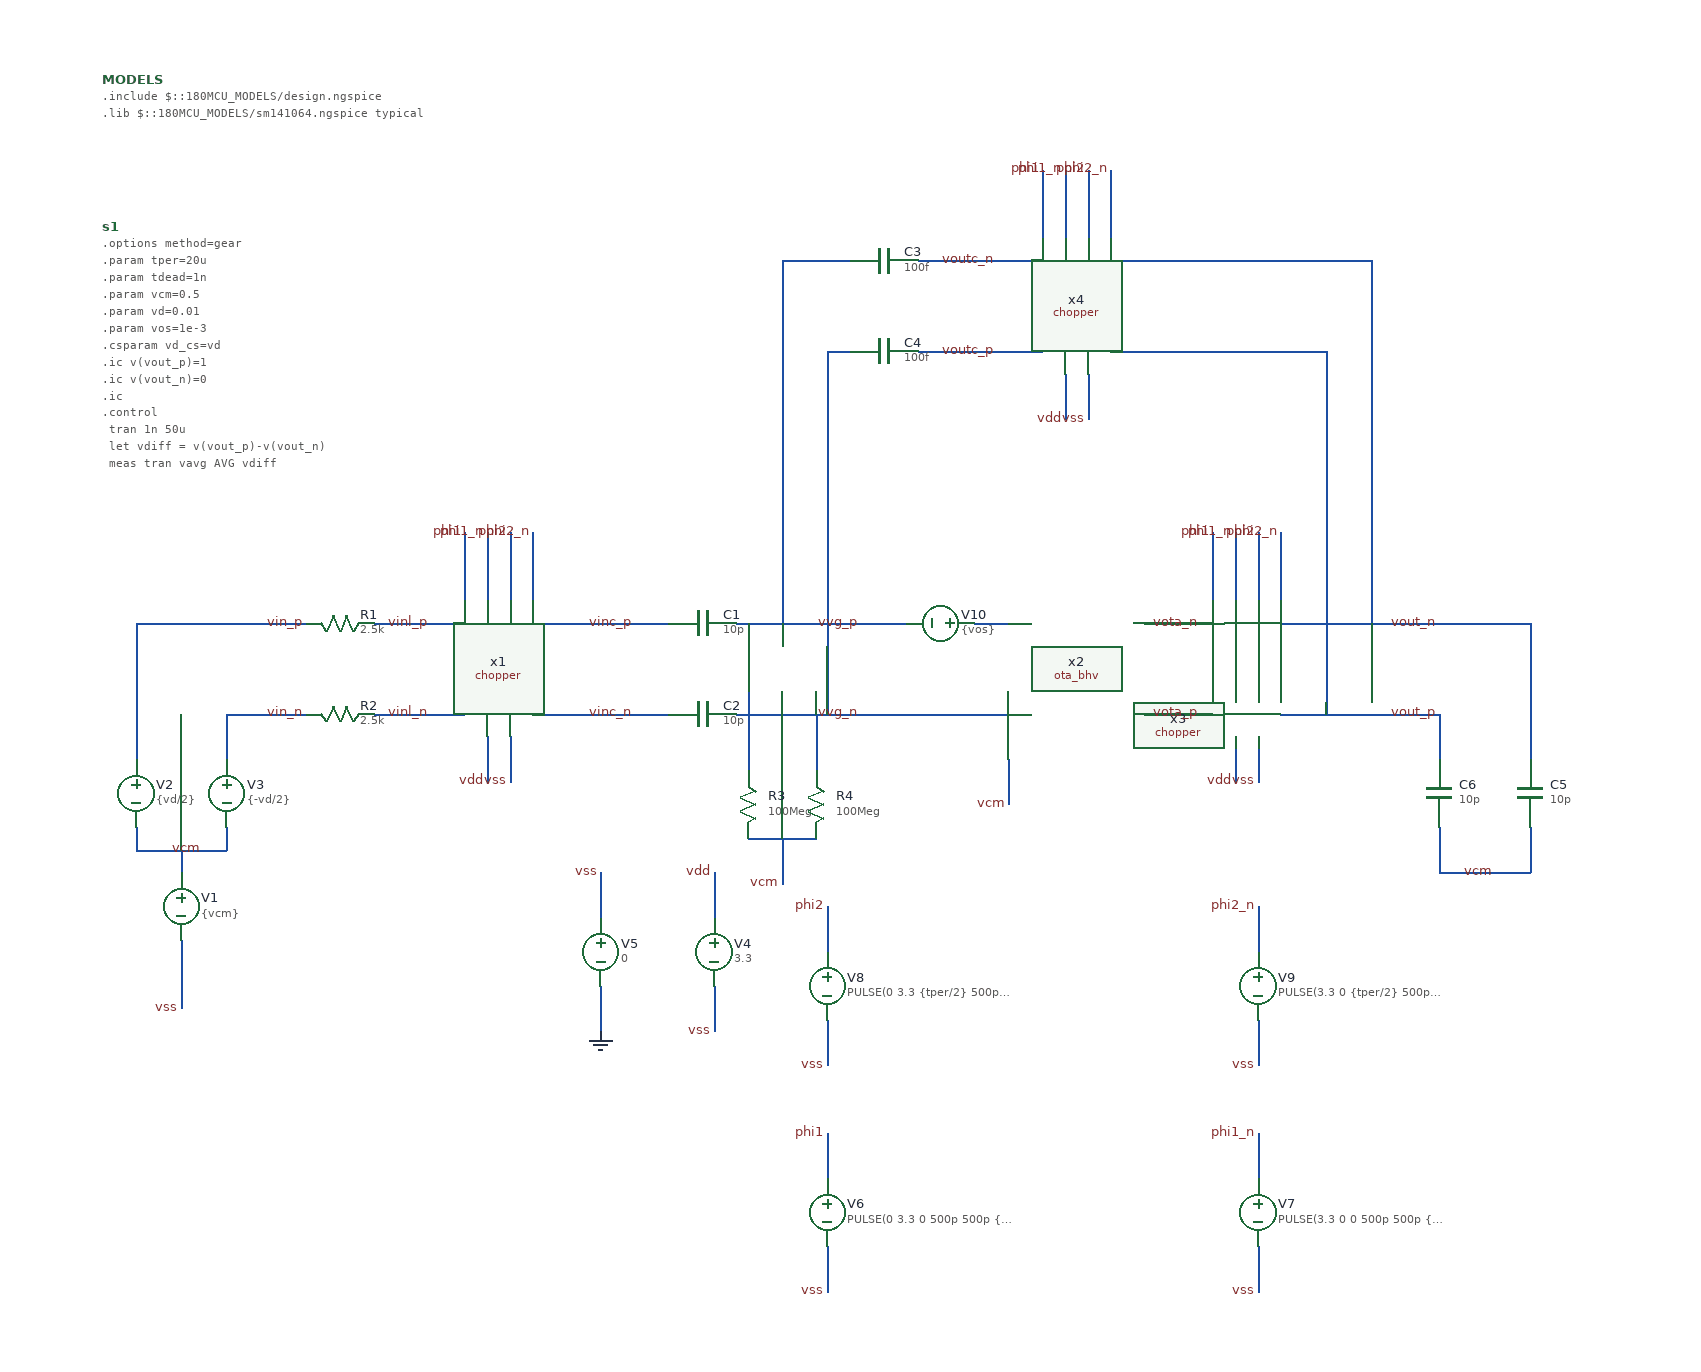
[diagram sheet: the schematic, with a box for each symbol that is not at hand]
v {xschem version=3.4.8RC file_version=1.3}
G {}
K {}
V {}
S {}
F {}
E {}
N 640 -160 860 -160 {lab=vout_n}
N 860 -160 860 -40 {lab=vout_n}
N 780 -80 780 -40 {lab=vout_p}
N 640 -80 780 -80 {lab=vout_p}
N 780 20 780 60 {lab=vcm}
N 780 60 860 60 {lab=vcm}
N 860 20 860 60 {lab=vcm}
N 400 -40 400 0 {lab=vcm}
N 520 -160 580 -160 {lab=vota_n}
N 520 -80 580 -80 {lab=vota_p}
N 160 -160 280 -160 {lab=vvg_p}
N 60 -160 100 -160 {lab=vinc_p}
N 60 -80 100 -80 {lab=vinc_n}
N 160 -80 280 -80 {lab=vvg_n}
N 720 -480 720 -160 {lab=vout_n}
N 680 -400 680 -80 {lab=vout_p}
N 320 -480 380 -480 {lab=voutc_n}
N 320 -400 380 -400 {lab=voutc_p}
N 200 -480 260 -480 {lab=vvg_p}
N 200 -480 200 -160 {lab=vvg_p}
N 240 -400 260 -400 {lab=vvg_n}
N 240 -400 240 -80 {lab=vvg_n}
N -60 -60 -60 -20 {lab=vdd}
N -40 -60 -40 -20 {lab=vss}
N 600 -60 600 -20 {lab=vdd}
N 620 -60 620 -20 {lab=vss}
N 450 -380 450 -340 {lab=vdd}
N 470 -380 470 -340 {lab=vss}
N -80 -220 -80 -180 {lab=phi1}
N -60 -220 -60 -180 {lab=phi1_n}
N -80 -240 -80 -220 {lab=phi1}
N -60 -240 -60 -220 {lab=phi1_n}
N -40 -220 -40 -180 {lab=phi2}
N -20 -220 -20 -180 {lab=phi2_n}
N -40 -240 -40 -220 {lab=phi2}
N -20 -240 -20 -220 {lab=phi2_n}
N 430 -540 430 -500 {lab=phi1}
N 450 -540 450 -500 {lab=phi1_n}
N 430 -560 430 -540 {lab=phi1}
N 450 -560 450 -540 {lab=phi1_n}
N 470 -540 470 -500 {lab=phi2}
N 490 -540 490 -500 {lab=phi2_n}
N 470 -560 470 -540 {lab=phi2}
N 490 -560 490 -540 {lab=phi2_n}
N 580 -220 580 -180 {lab=phi1}
N 600 -220 600 -180 {lab=phi1_n}
N 580 -240 580 -220 {lab=phi1}
N 600 -240 600 -220 {lab=phi1_n}
N 620 -220 620 -180 {lab=phi2}
N 640 -220 640 -180 {lab=phi2_n}
N 620 -240 620 -220 {lab=phi2}
N 640 -240 640 -220 {lab=phi2_n}
N -290 -80 -290 -40 {lab=vin_n}
N -290 -80 -230 -80 {lab=vin_n}
N -370 -160 -230 -160 {lab=vin_p}
N -370 -160 -370 -40 {lab=vin_p}
N -370 20 -370 40 {lab=vcm}
N -370 40 -290 40 {lab=vcm}
N -290 20 -290 40 {lab=vcm}
N -330 40 -330 60 {lab=vcm}
N -330 120 -330 180 {lab=vss}
N 140 160 140 180 {lab=vss}
N 140 180 140 200 {lab=vss}
N 140 60 140 100 {lab=vdd}
N 40 160 40 200 {lab=0}
N 40 80 40 100 {lab=vss}
N 40 60 40 80 {lab=vss}
N 240 390 240 410 {lab=vss}
N 240 410 240 430 {lab=vss}
N 240 290 240 330 {lab=phi1}
N 620 390 620 410 {lab=vss}
N 620 410 620 430 {lab=vss}
N 620 290 620 330 {lab=phi1_n}
N 240 190 240 210 {lab=vss}
N 240 210 240 230 {lab=vss}
N 240 90 240 130 {lab=phi2}
N 620 190 620 210 {lab=vss}
N 620 210 620 230 {lab=vss}
N 620 90 620 130 {lab=phi2_n}
N -230 -80 -220 -80 {lab=vin_n}
N -230 -160 -220 -160 {lab=vin_p}
N 170 30 230 30 {lab=vcm}
N 200 30 200 50 {lab=vcm}
N 200 50 200 70 {lab=vcm}
N 170 -160 170 -30 {lab=vvg_p}
N 230 -80 230 -30 {lab=vvg_n}
N 490 -480 600 -480 {lab=vout_n}
N 490 -400 560 -400 {lab=vout_p}
N 380 -400 420 -400 {lab=voutc_p}
N 420 -400 430 -400 {lab=voutc_p}
N 380 -480 430 -480 {lab=voutc_n}
N -160 -160 -80 -160 {lab=vinl_p}
N -160 -80 -80 -80 {lab=vinl_n}
N -20 -160 60 -160 {lab=vinc_p}
N -20 -80 60 -80 {lab=vinc_n}
N 280 -80 400 -80 {lab=vvg_n}
N 560 -400 680 -400 {lab=vout_p}
N 600 -480 720 -480 {lab=vout_n}
N 280 -160 310 -160 {lab=vvg_p}
N 370 -160 390 -160 {lab=#net1}
N 390 -160 400 -160 {lab=#net1}
C {chopper/chopper.sym} -80 -60 0 0 {name=x1}
C {ota_bhv/ota_bhv.sym} 400 -40 0 0 {name=x2 rout=1e6 dc_gain=1e6}
C {chopper/chopper.sym} 580 -60 0 0 {name=x3}
C {chopper/chopper.sym} 430 -380 0 0 {name=x4}
C {capa.sym} 130 -160 3 0 {name=C1
m=1
value=10p
footprint=1206
device="ceramic capacitor"}
C {capa.sym} 130 -80 3 0 {name=C2
m=1
value=10p
footprint=1206
device="ceramic capacitor"}
C {capa.sym} 290 -480 3 0 {name=C3
m=1
value=100f
footprint=1206
device="ceramic capacitor"}
C {capa.sym} 290 -400 3 0 {name=C4
m=1
value=100f
footprint=1206
device="ceramic capacitor"}
C {capa.sym} 860 -10 0 0 {name=C5
m=1
value=10p
footprint=1206
device="ceramic capacitor"}
C {capa.sym} 780 -10 0 0 {name=C6
m=1
value=10p

footprint=1206
device="ceramic capacitor"}
C {lab_wire.sym} 830 60 0 0 {name=p1 sig_type=std_logic lab=vcm}
C {lab_wire.sym} 400 0 1 0 {name=p2 sig_type=std_logic lab=vcm}
C {lab_wire.sym} 780 -160 0 0 {name=p3 sig_type=std_logic lab=vout_n}
C {lab_wire.sym} 780 -80 0 0 {name=p4 sig_type=std_logic lab=vout_p}
C {res.sym} -190 -160 1 0 {name=R1
value=2.5k
footprint=1206
device=resistor
m=1}
C {res.sym} -190 -80 1 0 {name=R2
value=2.5k
footprint=1206
device=resistor
m=1}
C {lab_wire.sym} -60 -20 3 1 {name=p5 sig_type=std_logic lab=vdd}
C {lab_wire.sym} -40 -20 3 1 {name=p6 sig_type=std_logic lab=vss}
C {lab_wire.sym} 600 -20 3 1 {name=p7 sig_type=std_logic lab=vdd}
C {lab_wire.sym} 620 -20 3 1 {name=p8 sig_type=std_logic lab=vss}
C {lab_wire.sym} 450 -340 3 1 {name=p9 sig_type=std_logic lab=vdd}
C {lab_wire.sym} 470 -340 3 1 {name=p10 sig_type=std_logic lab=vss}
C {lab_wire.sym} -80 -240 3 0 {name=p11 sig_type=std_logic lab=phi1}
C {lab_wire.sym} -60 -240 3 0 {name=p12 sig_type=std_logic lab=phi1_n}
C {lab_wire.sym} -40 -240 3 0 {name=p13 sig_type=std_logic lab=phi2}
C {lab_wire.sym} -20 -240 3 0 {name=p14 sig_type=std_logic lab=phi2_n}
C {lab_wire.sym} 430 -560 3 0 {name=p15 sig_type=std_logic lab=phi1}
C {lab_wire.sym} 450 -560 3 0 {name=p16 sig_type=std_logic lab=phi1_n}
C {lab_wire.sym} 470 -560 3 0 {name=p17 sig_type=std_logic lab=phi2}
C {lab_wire.sym} 490 -560 3 0 {name=p18 sig_type=std_logic lab=phi2_n}
C {lab_wire.sym} 580 -240 3 0 {name=p19 sig_type=std_logic lab=phi1}
C {lab_wire.sym} 600 -240 3 0 {name=p20 sig_type=std_logic lab=phi1_n}
C {lab_wire.sym} 620 -240 3 0 {name=p21 sig_type=std_logic lab=phi2}
C {lab_wire.sym} 640 -240 3 0 {name=p22 sig_type=std_logic lab=phi2_n}
C {vsource.sym} -330 90 0 0 {name=V1 value=\{vcm\} savecurrent=false}
C {vsource.sym} -370 -10 0 0 {name=V2 value=\{vd/2\} savecurrent=false}
C {vsource.sym} -290 -10 0 0 {name=V3 value=\{-vd/2\} savecurrent=false}
C {lab_wire.sym} -330 180 3 1 {name=p23 sig_type=std_logic lab=vss}
C {lab_wire.sym} -310 40 0 0 {name=p24 sig_type=std_logic lab=vcm}
C {lab_wire.sym} -220 -160 0 0 {name=p25 sig_type=std_logic lab=vin_p}
C {lab_wire.sym} -220 -80 0 0 {name=p26 sig_type=std_logic lab=vin_n}
C {vsource.sym} 140 130 0 0 {name=V4 value=3.3 savecurrent=false}
C {lab_wire.sym} 140 200 3 1 {name=p27 sig_type=std_logic lab=vss}
C {lab_wire.sym} 140 60 3 0 {name=p28 sig_type=std_logic lab=vdd}
C {vsource.sym} 40 130 0 0 {name=V5 value=0 savecurrent=false}
C {lab_wire.sym} 40 60 3 0 {name=p29 sig_type=std_logic lab=vss}
C {gnd.sym} 40 200 0 0 {name=l1 lab=0}
C {vsource.sym} 240 360 0 0 {name=V6 value="PULSE(0 3.3 0 500p 500p \{tper/2-tdead-500p\} \{tper\})" savecurrent=false}
C {lab_wire.sym} 240 430 3 1 {name=p30 sig_type=std_logic lab=vss}
C {lab_wire.sym} 240 290 1 1 {name=p31 sig_type=std_logic lab=phi1}
C {vsource.sym} 620 360 0 0 {name=V7 value="PULSE(3.3 0 0 500p 500p \{tper/2-tdead-500p\} \{tper\})" savecurrent=false}
C {lab_wire.sym} 620 430 3 1 {name=p32 sig_type=std_logic lab=vss}
C {lab_wire.sym} 620 290 1 1 {name=p33 sig_type=std_logic lab=phi1_n}
C {vsource.sym} 240 160 0 0 {name=V8 value="PULSE(0 3.3 \{tper/2\} 500p 500p \{tper/2-tdead-500p\} \{tper\})" savecurrent=false}
C {lab_wire.sym} 240 230 3 1 {name=p34 sig_type=std_logic lab=vss}
C {lab_wire.sym} 240 90 1 1 {name=p35 sig_type=std_logic lab=phi2}
C {vsource.sym} 620 160 0 0 {name=V9 value="PULSE(3.3 0 \{tper/2\} 500p 500p \{tper/2-tdead-500p\} \{tper\})" savecurrent=false}
C {lab_wire.sym} 620 230 3 1 {name=p36 sig_type=std_logic lab=vss}
C {lab_wire.sym} 620 90 1 1 {name=p37 sig_type=std_logic lab=phi2_n}
C {devices/code_shown.sym} -400 -640 0 0 {name=MODELS only_toplevel=true
format="tcleval( @value )"
value="
.include $::180MCU_MODELS/design.ngspice
.lib $::180MCU_MODELS/sm141064.ngspice typical
"}
C {code_shown.sym} -400 -510 0 0 {name=s1 only_toplevel=false value=".options method=gear
.param tper=20u
.param tdead=1n
.param vcm=0.5
.param vd=0.01
.param vos=1e-3
.csparam vd_cs=vd
.ic v(vout_p)=1
.ic v(vout_n)=0
.ic
.control
	tran 1n 50u
	let vdiff = v(vout_p)-v(vout_n)
        meas tran vavg AVG vdiff
	let error = 100*vd_cs-vavg
        echo \\"$&error\\"
.endc"}
C {res.sym} 170 0 0 0 {name=R3
value=100Meg
footprint=1206
device=resistor
m=1}
C {res.sym} 230 0 0 0 {name=R4
value=100Meg
footprint=1206
device=resistor
m=1}
C {lab_wire.sym} 200 70 1 0 {name=p38 sig_type=std_logic lab=vcm}
C {lab_wire.sym} 570 -80 0 0 {name=p39 sig_type=std_logic lab=vota_p}
C {lab_wire.sym} 570 -160 0 0 {name=p40 sig_type=std_logic lab=vota_n}
C {lab_wire.sym} 270 -160 0 0 {name=p41 sig_type=std_logic lab=vvg_p}
C {lab_wire.sym} 270 -80 0 0 {name=p42 sig_type=std_logic lab=vvg_n}
C {lab_wire.sym} 390 -480 0 0 {name=p43 sig_type=std_logic lab=voutc_n}
C {lab_wire.sym} 390 -400 0 0 {name=p44 sig_type=std_logic lab=voutc_p}
C {lab_wire.sym} -110 -160 0 0 {name=p45 sig_type=std_logic lab=vinl_p}
C {lab_wire.sym} -110 -80 0 0 {name=p46 sig_type=std_logic lab=vinl_n}
C {lab_wire.sym} 70 -160 0 0 {name=p47 sig_type=std_logic lab=vinc_p}
C {lab_wire.sym} 70 -80 0 0 {name=p48 sig_type=std_logic lab=vinc_n}
C {vsource.sym} 340 -160 1 0 {name=V10 value=\{vos\} savecurrent=false}
